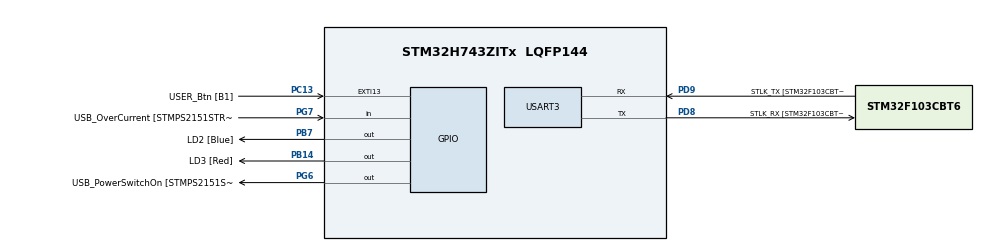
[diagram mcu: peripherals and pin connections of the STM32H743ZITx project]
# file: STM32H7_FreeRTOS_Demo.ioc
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Mcu.Family=STM32H7
Mcu.Name=STM32H743ZITx
Mcu.Package=LQFP144
NVIC.PriorityGroup=NVIC_PRIORITYGROUP_4
NVIC.TIM2_IRQn=true\:15\:0\:false\:false\:true\:false\:true
NVIC.TimeBase=TIM2_IRQn
NVIC.TimeBaseIP=TIM2
PA1.GPIO_Label=RMII_REF_CLK
PA1.Signal=ETH_REF_CLK
PA10.GPIO_Label=USB_ID
PA10.Signal=USB_OTG_FS_ID
PA11.GPIO_Label=USB_DM
PA11.Signal=USB_OTG_FS_DM
PA12.GPIO_Label=USB_DP
PA12.Signal=USB_OTG_FS_DP
PA2.GPIO_Label=RMII_MDIO
PA2.Signal=ETH_MDIO
PA7.GPIO_Label=RMII_CRS_DV
PA7.Signal=ETH_CRS_DV
PA8.GPIO_Label=USB_SOF [TP1]
PA8.Signal=USB_OTG_FS_SOF
PA9.GPIO_Label=USB_VBUS
PA9.Signal=USB_OTG_FS_VBUS
PB13.GPIO_Label=RMII_TXD1
PB13.Signal=ETH_TXD1
PB14.GPIO_Label=LD3 [Red]
PB14.Signal=GPIO_Output
PB7.GPIO_Label=LD2 [Blue]
PB7.Signal=GPIO_Output
PC1.GPIO_Label=RMII_MDC
PC1.Signal=ETH_MDC
PC13.GPIO_Label=USER_Btn [B1]
PC13.Signal=GPXTI13
PC14-OSC32_IN\ (OSC32_IN).Mode=LSE-External-Oscillator
PC14-OSC32_IN\ (OSC32_IN).Signal=RCC_OSC32_IN
PC15-OSC32_OUT\ (OSC32_OUT).Mode=LSE-External-Oscillator
PC15-OSC32_OUT\ (OSC32_OUT).Signal=RCC_OSC32_OUT
PC4.GPIO_Label=RMII_RXD0
PC4.Signal=ETH_RXD0
PC5.GPIO_Label=RMII_RXD1
PC5.Signal=ETH_RXD1
PD8.GPIO_Label=STLK_RX [STM32F103CBT6_PA3]
PD8.Mode=Asynchronous
PD8.Signal=USART3_TX
PD9.GPIO_Label=STLK_TX [STM32F103CBT6_PA2]
PD9.Mode=Asynchronous
PD9.Signal=USART3_RX
PG11.GPIO_Label=RMII_TX_EN
PG11.Signal=ETH_TX_EN
PG13.GPIO_Label=RMII_TXD0
PG13.Signal=ETH_TXD0
PG6.GPIO_Label=USB_PowerSwitchOn [STMPS2151STR_EN]
PG6.Signal=GPIO_Output
PG7.GPIO_Label=USB_OverCurrent [STMPS2151STR_FAULT]
PG7.Signal=GPIO_Input
PH0-OSC_IN\ (PH0).GPIO_Label=MCO
PH0-OSC_IN\ (PH0).Mode=HSE-External-Clock-Source
PH0-OSC_IN\ (PH0).Signal=RCC_OSC_IN
PH1-OSC_OUT\ (PH1).Signal=RCC_OSC_OUT
ProjectManager.HeapSize=0x2000
ProjectManager.StackSize=0x4000
ProjectManager.TargetToolchain=Makefile
RCC.48MHZClocksFreq_Value=24000000
RCC.ADCFreq_Value=16125000
RCC.AHBFreq_Value=216000000
RCC.APB1CLKDivider=RCC_HCLK_DIV4
RCC.APB1Freq_Value=60000000
RCC.APB1TimFreq_Value=108000000
RCC.APB2CLKDivider=RCC_HCLK_DIV2
RCC.APB2Freq_Value=120000000
RCC.APB2TimFreq_Value=216000000
RCC.APB3Freq_Value=120000000
RCC.APB4Freq_Value=120000000
RCC.CortexFreq_Value=120000000
RCC.D2PPRE1=RCC_APB1_DIV2
RCC.DIVM1=1
RCC.DIVN1=30
RCC.DIVQ1=4
RCC.HCLKFreq_Value=120000000
RCC.HSE_VALUE=8000000
RCC.HSI_VALUE=64000000
RCC.PLLFRACN=0
RCC.PLLM=25
RCC.PLLMUL=RCC_PLL_MUL9
RCC.PLLN=432
RCC.PLLQ=9
RCC.PLLSourceVirtual=RCC_PLLSOURCE_HSE
RCC.PRESCALERUSB=RCC_USBCLKSOURCE_PLL_DIV1_5
RCC.PWR_Regulator_Voltage_Scale=PWR_REGULATOR_VOLTAGE_SCALE1
RCC.SYSCLKFreq_VALUE=120000000
RCC.SYSCLKSource=RCC_SYSCLKSOURCE_PLLCLK
RCC.SYSCLKSourceVirtual=RCC_SYSCLKSOURCE_PLLCLK
RCC.USBFreq_Value=60000000
RCC.VCOOutputFreq_Value=432000000
USART3.VirtualMode-Asynchronous=VM_ASYNC
VP_SYS_VS_tim2.Mode=TIM2
board=NUCLEO-H743ZI

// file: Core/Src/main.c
/* USER CODE BEGIN Header */
/**
  ******************************************************************************
  * @file           : main.c
  * @brief          : Main program body
  ******************************************************************************
  * @attention
  *
  * <h2><center>&copy; Copyright (c) 2021 STMicroelectronics.
  * All rights reserved.</center></h2>
  *
  * This software component is licensed by ST under BSD 3-Clause license,
  * the "License"; You may not use this file except in compliance with the
  * License. You may obtain a copy of the License at:
  *                        opensource.org/licenses/BSD-3-Clause
  *
  ******************************************************************************
  */
/* USER CODE END Header */
#include "main.h"
#include "usart.h"
#include "gpio.h"

/* USER CODE BEGIN Includes */
#include <stdio.h>
#include "FreeRTOS.h"
#include "task.h"

/* USER CODE END Includes */

void SystemClock_Config(void);

/* USER CODE BEGIN 0 */
#ifndef __ARMCC_VERSION
int _write(int file, char *ptr, int len)
{
  HAL_UART_Transmit((UART_HandleTypeDef *)&huart3, (uint8_t *)ptr, len, 1000 * len);
  return len;
}
#else
int fputc(int ch, FILE *f)
{
  /* Place your implementation of fputc here */
  /* e.g. write a character to the EVAL_COM1 and Loop until the end of transmission */
  HAL_UART_Transmit(&huart3, (uint8_t *)&ch, 1, 0xFFFF);

  return ch;
}
#endif /* __ARMCC_VERSION */

void HAL_IncTick(void)
{
  extern __IO uint32_t uwTick;
  uwTick += uwTickFreq;
  if ((uwTick & 255) == 0)
  {
    HAL_GPIO_TogglePin(LD3_GPIO_Port, LD3_Pin);
  }
}

void LedTask(void *pvParameters)
{

  while (1)
  {
    HAL_GPIO_TogglePin(LD2_GPIO_Port, LD2_Pin);
    vTaskDelay(255 / portTICK_RATE_MS);
  }
}

/* USER CODE END 0 */

int main(void)
{

  /* MCU Configuration--------------------------------------------------------*/

  /* Reset of all peripherals, Initializes the Flash interface and the Systick. */
  HAL_Init();

  /* Configure the system clock */
  SystemClock_Config();

  /* Initialize all configured peripherals */
  MX_GPIO_Init();
  MX_USART3_UART_Init();
  /* USER CODE BEGIN 2 */
  printf("system init...\n");
  /* USER CODE END 2 */

  /* Infinite loop */
  /* USER CODE BEGIN WHILE */
  while (1)
  {
    HAL_GPIO_TogglePin(LD2_GPIO_Port, LD2_Pin);
    HAL_Delay(500);

    //创建任务taskMain
    xTaskCreate(LedTask, "LedTask", configMINIMAL_STACK_SIZE, NULL, tskIDLE_PRIORITY + 2, NULL);

    // 启动任务调度
    vTaskStartScheduler();
    /* USER CODE END WHILE */

  }
}

void SystemClock_Config(void)
{
  RCC_OscInitTypeDef RCC_OscInitStruct = {0};
  RCC_ClkInitTypeDef RCC_ClkInitStruct = {0};

  /** Supply configuration update enable
  */
  HAL_PWREx_ConfigSupply(PWR_LDO_SUPPLY);
  /** Configure the main internal regulator output voltage
  */
  __HAL_PWR_VOLTAGESCALING_CONFIG(PWR_REGULATOR_VOLTAGE_SCALE1);

  while(!__HAL_PWR_GET_FLAG(PWR_FLAG_VOSRDY)) {}
  /** Initializes the RCC Oscillators according to the specified parameters
  * in the RCC_OscInitTypeDef structure.
  */
  RCC_OscInitStruct.OscillatorType = RCC_OSCILLATORTYPE_HSE;
  RCC_OscInitStruct.HSEState = RCC_HSE_BYPASS;
  RCC_OscInitStruct.PLL.PLLState = RCC_PLL_ON;
  RCC_OscInitStruct.PLL.PLLSource = RCC_PLLSOURCE_HSE;
  RCC_OscInitStruct.PLL.PLLM = 1;
  RCC_OscInitStruct.PLL.PLLN = 30;
  RCC_OscInitStruct.PLL.PLLP = 2;
  RCC_OscInitStruct.PLL.PLLQ = 2;
  RCC_OscInitStruct.PLL.PLLR = 2;
  RCC_OscInitStruct.PLL.PLLRGE = RCC_PLL1VCIRANGE_3;
  RCC_OscInitStruct.PLL.PLLVCOSEL = RCC_PLL1VCOWIDE;
  RCC_OscInitStruct.PLL.PLLFRACN = 0;
  if (HAL_RCC_OscConfig(&RCC_OscInitStruct) != HAL_OK)
  {
    Error_Handler();
  }
  /** Initializes the CPU, AHB and APB buses clocks
  */
  RCC_ClkInitStruct.ClockType = RCC_CLOCKTYPE_HCLK|RCC_CLOCKTYPE_SYSCLK
                              |RCC_CLOCKTYPE_PCLK1|RCC_CLOCKTYPE_PCLK2
                              |RCC_CLOCKTYPE_D3PCLK1|RCC_CLOCKTYPE_D1PCLK1;
  RCC_ClkInitStruct.SYSCLKSource = RCC_SYSCLKSOURCE_PLLCLK;
  RCC_ClkInitStruct.SYSCLKDivider = RCC_SYSCLK_DIV1;
  RCC_ClkInitStruct.AHBCLKDivider = RCC_HCLK_DIV1;
  RCC_ClkInitStruct.APB3CLKDivider = RCC_APB3_DIV2;
  RCC_ClkInitStruct.APB1CLKDivider = RCC_APB1_DIV2;
  RCC_ClkInitStruct.APB2CLKDivider = RCC_APB2_DIV2;
  RCC_ClkInitStruct.APB4CLKDivider = RCC_APB4_DIV2;

  if (HAL_RCC_ClockConfig(&RCC_ClkInitStruct, FLASH_LATENCY_1) != HAL_OK)
  {
    Error_Handler();
  }
}

void HAL_TIM_PeriodElapsedCallback(TIM_HandleTypeDef *htim)
{
  if (htim->Instance == TIM2) {
    HAL_IncTick();
  }
}

void Error_Handler(void)
{
  __disable_irq();
  while (1)
  {
  }
}

/************************ (C) COPYRIGHT STMicroelectronics *****END OF FILE****/
